VERSION 5.7 ;
  NOWIREEXTENSIONATPIN ON ;
  DIVIDERCHAR "/" ;
  BUSBITCHARS "[]" ;
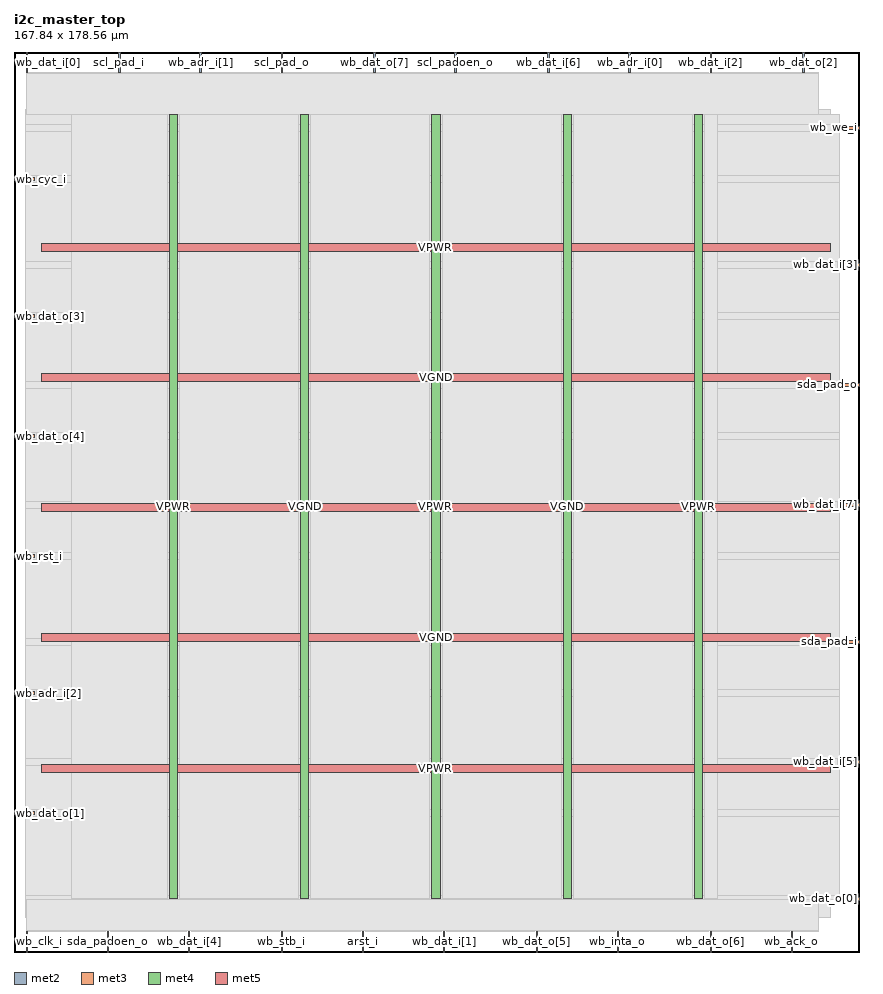
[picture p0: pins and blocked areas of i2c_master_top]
MACRO i2c_master_top
  CLASS BLOCK ;
  FOREIGN i2c_master_top ;
  ORIGIN 0.000 0.000 ;
  SIZE 167.840 BY 178.560 ;
  PIN arst_i
    DIRECTION INPUT ;
    USE SIGNAL ;
    PORT
      LAYER met2 ;
        RECT 69.090 0.000 69.370 4.000 ;
    END
  END arst_i
  PIN scl_pad_i
    DIRECTION INPUT ;
    USE SIGNAL ;
    PORT
      LAYER met2 ;
        RECT 20.790 174.560 21.070 178.560 ;
    END
  END scl_pad_i
  PIN scl_pad_o
    DIRECTION OUTPUT TRISTATE ;
    USE SIGNAL ;
    PORT
      LAYER met2 ;
        RECT 52.990 174.560 53.270 178.560 ;
    END
  END scl_pad_o
  PIN scl_padoen_o
    DIRECTION OUTPUT TRISTATE ;
    USE SIGNAL ;
    PORT
      LAYER met2 ;
        RECT 87.490 174.560 87.770 178.560 ;
    END
  END scl_padoen_o
  PIN sda_pad_i
    DIRECTION INPUT ;
    USE SIGNAL ;
    PORT
      LAYER met3 ;
        RECT 163.840 61.240 167.840 61.840 ;
    END
  END sda_pad_i
  PIN sda_pad_o
    DIRECTION OUTPUT TRISTATE ;
    USE SIGNAL ;
    PORT
      LAYER met3 ;
        RECT 163.840 112.240 167.840 112.840 ;
    END
  END sda_pad_o
  PIN sda_padoen_o
    DIRECTION OUTPUT TRISTATE ;
    USE SIGNAL ;
    PORT
      LAYER met2 ;
        RECT 18.490 0.000 18.770 4.000 ;
    END
  END sda_padoen_o
  PIN wb_ack_o
    DIRECTION OUTPUT TRISTATE ;
    USE SIGNAL ;
    PORT
      LAYER met2 ;
        RECT 154.190 0.000 154.470 4.000 ;
    END
  END wb_ack_o
  PIN wb_adr_i[0]
    DIRECTION INPUT ;
    USE SIGNAL ;
    PORT
      LAYER met2 ;
        RECT 121.990 174.560 122.270 178.560 ;
    END
  END wb_adr_i[0]
  PIN wb_adr_i[1]
    DIRECTION INPUT ;
    USE SIGNAL ;
    PORT
      LAYER met2 ;
        RECT 36.890 174.560 37.170 178.560 ;
    END
  END wb_adr_i[1]
  PIN wb_adr_i[2]
    DIRECTION INPUT ;
    USE SIGNAL ;
    PORT
      LAYER met3 ;
        RECT 0.000 51.040 4.000 51.640 ;
    END
  END wb_adr_i[2]
  PIN wb_clk_i
    DIRECTION INPUT ;
    USE SIGNAL ;
    PORT
      LAYER met2 ;
        RECT 2.390 0.000 2.670 4.000 ;
    END
  END wb_clk_i
  PIN wb_cyc_i
    DIRECTION INPUT ;
    USE SIGNAL ;
    PORT
      LAYER met3 ;
        RECT 0.000 153.040 4.000 153.640 ;
    END
  END wb_cyc_i
  PIN wb_dat_i[0]
    DIRECTION INPUT ;
    USE SIGNAL ;
    PORT
      LAYER met2 ;
        RECT 2.390 174.560 2.670 178.560 ;
    END
  END wb_dat_i[0]
  PIN wb_dat_i[1]
    DIRECTION INPUT ;
    USE SIGNAL ;
    PORT
      LAYER met2 ;
        RECT 85.190 0.000 85.470 4.000 ;
    END
  END wb_dat_i[1]
  PIN wb_dat_i[2]
    DIRECTION INPUT ;
    USE SIGNAL ;
    PORT
      LAYER met2 ;
        RECT 138.090 174.560 138.370 178.560 ;
    END
  END wb_dat_i[2]
  PIN wb_dat_i[3]
    DIRECTION INPUT ;
    USE SIGNAL ;
    PORT
      LAYER met3 ;
        RECT 163.840 136.040 167.840 136.640 ;
    END
  END wb_dat_i[3]
  PIN wb_dat_i[4]
    DIRECTION INPUT ;
    USE SIGNAL ;
    PORT
      LAYER met2 ;
        RECT 34.590 0.000 34.870 4.000 ;
    END
  END wb_dat_i[4]
  PIN wb_dat_i[5]
    DIRECTION INPUT ;
    USE SIGNAL ;
    PORT
      LAYER met3 ;
        RECT 163.840 37.440 167.840 38.040 ;
    END
  END wb_dat_i[5]
  PIN wb_dat_i[6]
    DIRECTION INPUT ;
    USE SIGNAL ;
    PORT
      LAYER met2 ;
        RECT 105.890 174.560 106.170 178.560 ;
    END
  END wb_dat_i[6]
  PIN wb_dat_i[7]
    DIRECTION INPUT ;
    USE SIGNAL ;
    PORT
      LAYER met3 ;
        RECT 163.840 88.440 167.840 89.040 ;
    END
  END wb_dat_i[7]
  PIN wb_dat_o[0]
    DIRECTION OUTPUT TRISTATE ;
    USE SIGNAL ;
    PORT
      LAYER met3 ;
        RECT 163.840 10.240 167.840 10.840 ;
    END
  END wb_dat_o[0]
  PIN wb_dat_o[1]
    DIRECTION OUTPUT TRISTATE ;
    USE SIGNAL ;
    PORT
      LAYER met3 ;
        RECT 0.000 27.240 4.000 27.840 ;
    END
  END wb_dat_o[1]
  PIN wb_dat_o[2]
    DIRECTION OUTPUT TRISTATE ;
    USE SIGNAL ;
    PORT
      LAYER met2 ;
        RECT 156.490 174.560 156.770 178.560 ;
    END
  END wb_dat_o[2]
  PIN wb_dat_o[3]
    DIRECTION OUTPUT TRISTATE ;
    USE SIGNAL ;
    PORT
      LAYER met3 ;
        RECT 0.000 125.840 4.000 126.440 ;
    END
  END wb_dat_o[3]
  PIN wb_dat_o[4]
    DIRECTION OUTPUT TRISTATE ;
    USE SIGNAL ;
    PORT
      LAYER met3 ;
        RECT 0.000 102.040 4.000 102.640 ;
    END
  END wb_dat_o[4]
  PIN wb_dat_o[5]
    DIRECTION OUTPUT TRISTATE ;
    USE SIGNAL ;
    PORT
      LAYER met2 ;
        RECT 103.590 0.000 103.870 4.000 ;
    END
  END wb_dat_o[5]
  PIN wb_dat_o[6]
    DIRECTION OUTPUT TRISTATE ;
    USE SIGNAL ;
    PORT
      LAYER met2 ;
        RECT 138.090 0.000 138.370 4.000 ;
    END
  END wb_dat_o[6]
  PIN wb_dat_o[7]
    DIRECTION OUTPUT TRISTATE ;
    USE SIGNAL ;
    PORT
      LAYER met2 ;
        RECT 71.390 174.560 71.670 178.560 ;
    END
  END wb_dat_o[7]
  PIN wb_inta_o
    DIRECTION OUTPUT TRISTATE ;
    USE SIGNAL ;
    PORT
      LAYER met2 ;
        RECT 119.690 0.000 119.970 4.000 ;
    END
  END wb_inta_o
  PIN wb_rst_i
    DIRECTION INPUT ;
    USE SIGNAL ;
    PORT
      LAYER met3 ;
        RECT 0.000 78.240 4.000 78.840 ;
    END
  END wb_rst_i
  PIN wb_stb_i
    DIRECTION INPUT ;
    USE SIGNAL ;
    PORT
      LAYER met2 ;
        RECT 52.990 0.000 53.270 4.000 ;
    END
  END wb_stb_i
  PIN wb_we_i
    DIRECTION INPUT ;
    USE SIGNAL ;
    PORT
      LAYER met3 ;
        RECT 163.840 163.240 167.840 163.840 ;
    END
  END wb_we_i
  PIN VPWR
    DIRECTION INOUT ;
    USE POWER ;
    PORT
      LAYER met4 ;
        RECT 135.055 10.640 136.655 166.160 ;
    END
  END VPWR
  PIN VPWR
    DIRECTION INOUT ;
    USE POWER ;
    PORT
      LAYER met4 ;
        RECT 82.920 10.640 84.520 166.160 ;
    END
  END VPWR
  PIN VPWR
    DIRECTION INOUT ;
    USE POWER ;
    PORT
      LAYER met4 ;
        RECT 30.785 10.640 32.385 166.160 ;
    END
  END VPWR
  PIN VPWR
    DIRECTION INOUT ;
    USE POWER ;
    PORT
      LAYER met5 ;
        RECT 5.520 139.040 161.920 140.640 ;
    END
  END VPWR
  PIN VPWR
    DIRECTION INOUT ;
    USE POWER ;
    PORT
      LAYER met5 ;
        RECT 5.520 87.360 161.920 88.960 ;
    END
  END VPWR
  PIN VPWR
    DIRECTION INOUT ;
    USE POWER ;
    PORT
      LAYER met5 ;
        RECT 5.520 35.680 161.920 37.280 ;
    END
  END VPWR
  PIN VGND
    DIRECTION INOUT ;
    USE GROUND ;
    PORT
      LAYER met4 ;
        RECT 108.985 10.640 110.585 166.160 ;
    END
  END VGND
  PIN VGND
    DIRECTION INOUT ;
    USE GROUND ;
    PORT
      LAYER met4 ;
        RECT 56.855 10.640 58.455 166.160 ;
    END
  END VGND
  PIN VGND
    DIRECTION INOUT ;
    USE GROUND ;
    PORT
      LAYER met5 ;
        RECT 5.520 113.200 161.920 114.800 ;
    END
  END VGND
  PIN VGND
    DIRECTION INOUT ;
    USE GROUND ;
    PORT
      LAYER met5 ;
        RECT 5.520 61.520 161.920 63.120 ;
    END
  END VGND
  OBS
      LAYER li1 ;
        RECT 5.520 10.795 161.920 166.005 ;
      LAYER met1 ;
        RECT 2.370 6.840 161.920 167.240 ;
      LAYER met2 ;
        RECT 2.950 174.280 20.510 174.560 ;
        RECT 21.350 174.280 36.610 174.560 ;
        RECT 37.450 174.280 52.710 174.560 ;
        RECT 53.550 174.280 71.110 174.560 ;
        RECT 71.950 174.280 87.210 174.560 ;
        RECT 88.050 174.280 105.610 174.560 ;
        RECT 106.450 174.280 121.710 174.560 ;
        RECT 122.550 174.280 137.810 174.560 ;
        RECT 138.650 174.280 156.210 174.560 ;
        RECT 157.050 174.280 159.520 174.560 ;
        RECT 2.390 4.280 159.520 174.280 ;
        RECT 2.950 4.000 18.210 4.280 ;
        RECT 19.050 4.000 34.310 4.280 ;
        RECT 35.150 4.000 52.710 4.280 ;
        RECT 53.550 4.000 68.810 4.280 ;
        RECT 69.650 4.000 84.910 4.280 ;
        RECT 85.750 4.000 103.310 4.280 ;
        RECT 104.150 4.000 119.410 4.280 ;
        RECT 120.250 4.000 137.810 4.280 ;
        RECT 138.650 4.000 153.910 4.280 ;
        RECT 154.750 4.000 159.520 4.280 ;
      LAYER met3 ;
        RECT 2.365 164.240 163.840 166.085 ;
        RECT 2.365 162.840 163.440 164.240 ;
        RECT 2.365 154.040 163.840 162.840 ;
        RECT 4.400 152.640 163.840 154.040 ;
        RECT 2.365 137.040 163.840 152.640 ;
        RECT 2.365 135.640 163.440 137.040 ;
        RECT 2.365 126.840 163.840 135.640 ;
        RECT 4.400 125.440 163.840 126.840 ;
        RECT 2.365 113.240 163.840 125.440 ;
        RECT 2.365 111.840 163.440 113.240 ;
        RECT 2.365 103.040 163.840 111.840 ;
        RECT 4.400 101.640 163.840 103.040 ;
        RECT 2.365 89.440 163.840 101.640 ;
        RECT 2.365 88.040 163.440 89.440 ;
        RECT 2.365 79.240 163.840 88.040 ;
        RECT 4.400 77.840 163.840 79.240 ;
        RECT 2.365 62.240 163.840 77.840 ;
        RECT 2.365 60.840 163.440 62.240 ;
        RECT 2.365 52.040 163.840 60.840 ;
        RECT 4.400 50.640 163.840 52.040 ;
        RECT 2.365 38.440 163.840 50.640 ;
        RECT 2.365 37.040 163.440 38.440 ;
        RECT 2.365 28.240 163.840 37.040 ;
        RECT 4.400 26.840 163.840 28.240 ;
        RECT 2.365 11.240 163.840 26.840 ;
        RECT 2.365 10.375 163.440 11.240 ;
      LAYER met4 ;
        RECT 11.335 10.640 30.385 166.160 ;
        RECT 32.785 10.640 56.455 166.160 ;
        RECT 58.855 10.640 82.520 166.160 ;
        RECT 84.920 10.640 108.585 166.160 ;
        RECT 110.985 10.640 134.655 166.160 ;
        RECT 137.055 10.640 139.545 166.160 ;
  END
END i2c_master_top
END LIBRARY

